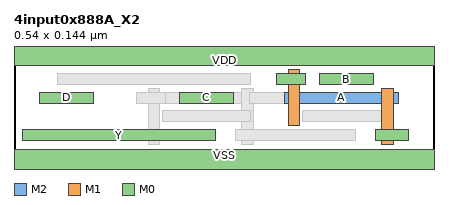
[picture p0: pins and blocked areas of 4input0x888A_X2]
MACRO 4input0x888A_X2
  CLASS CORE ;
  ORIGIN 0 0 ;
  FOREIGN 4input0x888A_X2 0 0 ;
  SIZE 0.5400 BY 0.1440 ;
  SYMMETRY X Y ;
  SITE coresite ;
  PIN A
    DIRECTION INPUT ;
    USE SIGNAL ;
    PORT
      LAYER M2 ;
        RECT 0.3480 0.0770 0.4950 0.0910 ;
      LAYER M1 ;
        RECT 0.3525 0.0480 0.3675 0.1200 ;
        RECT 0.4725 0.0240 0.4875 0.0960 ;
      LAYER M0 ;
        RECT 0.4650 0.0290 0.5070 0.0430 ;
        RECT 0.3375 0.1010 0.3750 0.1150 ;
    END
  END A
  PIN B
    DIRECTION INPUT ;
    USE SIGNAL ;
    PORT
      LAYER M0 ;
        RECT 0.3930 0.1010 0.4620 0.1150 ;
    END
  END B
  PIN C
    DIRECTION INPUT ;
    USE SIGNAL ;
    PORT
      LAYER M0 ;
        RECT 0.2130 0.0770 0.2820 0.0910 ;
    END
  END C
  PIN D
    DIRECTION INPUT ;
    USE SIGNAL ;
    PORT
      LAYER M0 ;
        RECT 0.0330 0.0770 0.1020 0.0910 ;
    END
  END D
  PIN Y
    DIRECTION OUTPUT ;
    USE SIGNAL ;
    PORT
      LAYER M0 ;
        RECT 0.0105 0.0290 0.2595 0.0430 ;
    END
  END Y
  PIN VDD
    DIRECTION INOUT ;
    USE POWER ;
    SHAPE ABUTMENT ;
    PORT
      LAYER M0 ;
        RECT 0.0000 0.1260 0.5400 0.1620 ;
    END
  END VDD
  PIN VSS
    DIRECTION INOUT ;
    USE GROUND ;
    SHAPE ABUTMENT ;
    PORT
      LAYER M0 ;
        RECT 0.0000 -0.0180 0.5400 0.0180 ;
    END
  END VSS
  OBS
    LAYER M2 ;
      RECT 0.1680 0.0770 0.3150 0.0910 ;
    LAYER V1 ;
      RECT 0.3530 0.0770 0.3670 0.0910 ;
      RECT 0.4730 0.0770 0.4870 0.0910 ;
      RECT 0.1730 0.0770 0.1870 0.0910 ;
      RECT 0.2930 0.0770 0.3070 0.0910 ;
    LAYER M1 ;
      RECT 0.1725 0.0240 0.1875 0.0960 ;
      RECT 0.2925 0.0240 0.3075 0.0960 ;
    LAYER V0 ;
      RECT 0.3530 0.1010 0.3670 0.1150 ;
      RECT 0.4730 0.0290 0.4870 0.0430 ;
      RECT 0.1730 0.0770 0.1870 0.0910 ;
      RECT 0.2930 0.0290 0.3070 0.0430 ;
    LAYER M0 ;
      RECT 0.2850 0.0290 0.4395 0.0430 ;
      RECT 0.1905 0.0530 0.3045 0.0670 ;
      RECT 0.3705 0.0530 0.4845 0.0670 ;
      RECT 0.1575 0.0770 0.1950 0.0910 ;
      RECT 0.3030 0.0770 0.4845 0.0910 ;
      RECT 0.0555 0.1010 0.3045 0.1150 ;
  END
END 4input0x888A_X2
